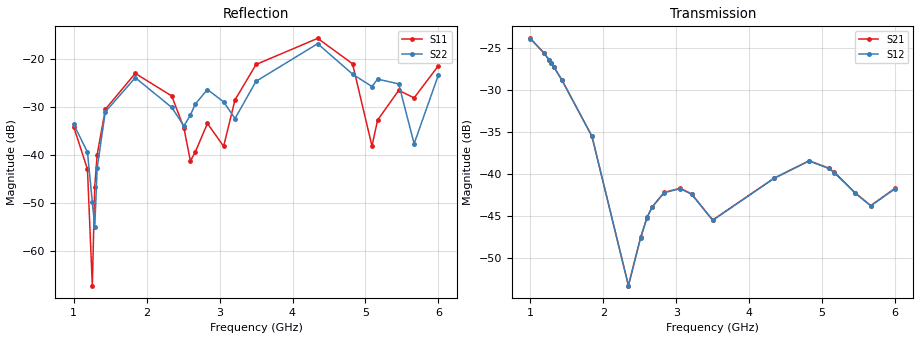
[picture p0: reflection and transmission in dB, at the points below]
!Agilent Technologies,E8364B,MY43040528,A.07.50.67
!Agilent E8364B: A.07.50.67
!Date: Sunday, March 01, 2026 16:56:53
!Correction: S11(Full 2 Port(1,2))
!S21(Full 2 Port(1,2))
!S12(Full 2 Port(1,2))
!S22(Full 2 Port(1,2))
!S2P File: Measurements: S11, S21, S12, S22:
# Hz S  dB  R 50
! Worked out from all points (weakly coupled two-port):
!   451 points, 1 GHz to 6 GHz, reference 50 ohm
!   highest |S21| = -23.80 dB at 1 GHz (marker M1); lowest = -53.2 dB at 2.344 GHz (marker M2)
!   lowest |S11| = -67.2 dB at 1.256 GHz (marker M3), VSWR 1.00, Z = 50 - j0.0304 ohm
!   |S11| at or under -10 dB: start of sweep to end of sweep
!   |S22| runs from -64.9 to -16.7 dB; largest |S21 - S12| = 0.00029
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1e9  -34.10 25.6  -23.80 152.9  -23.84 152.9  -33.57 -2.9
1.188889e9  -42.94 25.5  -25.56 45.0  -25.59 45.0  -39.39 -8.7
1.255556e9  -67.20 -44.1  -26.33 7.1  -26.36 7.2  -49.79 -17.1
1.288889e9  -46.57 -157.5  -26.74 -11.7  -26.78 -11.6  -54.98 124.3
1.322222e9  -39.91 -166.2  -27.18 -30.4  -27.22 -30.3  -42.61 128.8
1.433333e9  -30.48 164.4  -28.76 -91.8  -28.79 -91.8  -31.01 101.2
1.844444e9  -22.99 77.2  -35.44 47.9  -35.47 48.0  -23.88 -5.2
2.344444e9  -27.69 4.8  -53.24 -150.5  -53.22 -150.9  -30.07 -84.6
2.511111e9  -34.35 -13.6  -47.50 178.9  -47.55 179.2  -33.94 -69.2
2.6e9  -41.22 13.4  -45.11 137.9  -45.14 138.1  -31.67 -56.1
2.666667e9  -39.37 56.4  -43.90 104.5  -43.92 104.6  -29.38 -59.6
2.833333e9  -33.40 54.2  -42.14 17.7  -42.17 17.7  -26.35 -91.2
3.055556e9  -38.18 80.5  -41.64 -100.5  -41.69 -100.4  -28.91 -133.6
3.211111e9  -28.51 107.7  -42.32 177.4  -42.37 177.5  -32.39 -117.7
3.5e9  -21.13 62.5  -45.42 37.2  -45.46 37.2  -24.63 -128.5
4.344444e9  -15.69 -41.2  -40.42 22.6  -40.45 22.5  -16.80 111.5
4.822222e9  -20.97 -123.1  -38.37 114.4  -38.40 114.5  -23.13 31.5
5.088889e9  -38.11 -104.6  -39.24 -43.5  -39.28 -43.4  -25.72 45.8
5.166667e9  -32.69 -53.4  -39.74 -90.4  -39.78 -90.5  -24.18 39.4
5.455556e9  -26.52 -82.9  -42.21 85.9  -42.25 85.9  -25.17 -20.1
5.666667e9  -28.08 -70.1  -43.70 -63.1  -43.74 -63.1  -37.63 -6.5
6e9  -21.38 -78.7  -41.64 59.8  -41.69 59.8  -23.30 -0.5
